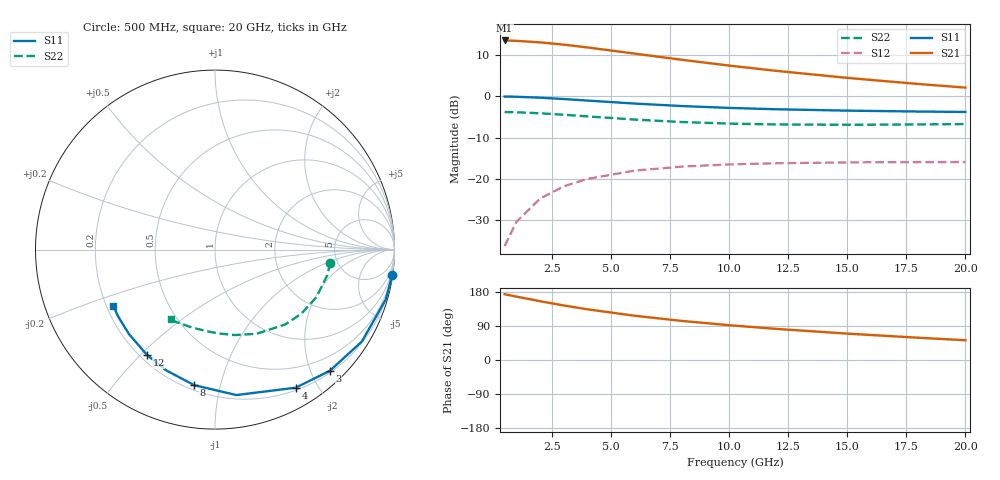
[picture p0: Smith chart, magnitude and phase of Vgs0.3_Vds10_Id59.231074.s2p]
# Hz S RI R 50
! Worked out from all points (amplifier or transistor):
!   12 points, 500 MHz to 20 GHz, reference 50 ohm
!   highest |S21| = 13.6 dB at 500 MHz (marker M1)
!   |S21| within 3 dB of that: start of sweep to 5.74 GHz
!   unconditionally stable (mu >= 1): nowhere
!   at 2 GHz: K = 0.10, MSG = 19.0 dB, |S12| = -24.8 dB
!   at 8 GHz: K = 0.38, MSG = 13.0 dB, |S12| = -17.1 dB
!   at 20 GHz: K = 0.99, MSG = 9.1 dB, |S12| = -16.0 dB
!   S11 on the Smith chart (normalised r, x): 500 MHz: 0, -14; 3 GHz: 0.23, -2.30; 4 GHz: 0.23, -1.72; 8 GHz: 0.23, -0.83; 12 GHz: 0.23, -0.52; 20 GHz: 0.23, -0.24
5e8  0.9874 -0.1428  -4.765 0.5334  0.00146 0.015  0.6424 -0.0731
1e9  0.9506 -0.2791  -4.625 1.042  0.0057 0.0293  0.6255 -0.1433
2e9  0.8182 -0.5124  -4.124 1.91  0.0209 0.0533  0.5643 -0.266
3e9  0.6394 -0.6755  -3.448 2.51  0.0414 0.0691  0.481 -0.3571
4e9  0.4497 -0.7694  -2.732 2.846  0.0631 0.0768  0.3917 -0.4169
6e9  0.119 -0.8104  -1.496 2.962  0.1001 0.0753  0.2312 -0.4692
8e9  -0.1162 -0.7552  -0.6331 2.717  0.1254 0.0628  0.1091 -0.4761
1e10  -0.2736 -0.6717  -0.075 2.372  0.1411 0.0476  0.018 -0.4669
1.2e10  -0.3795 -0.5861  0.2807 2.028  0.1504 0.0326  -0.053 -0.4532
1.5e10  -0.4802 -0.4699  0.5859 1.576  0.1572 0.0124  -0.1375 -0.4308
1.8e10  -0.5405 -0.3705  0.7349 1.212  0.1589 -0.00447  -0.2069 -0.4067
2e10  -0.5673 -0.3122  0.7844 1.011  0.1585 -0.0142  -0.2476 -0.3894
